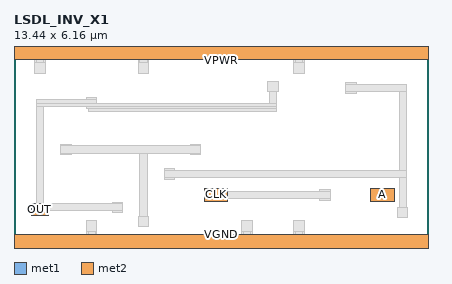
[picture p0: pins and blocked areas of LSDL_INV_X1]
MACRO LSDL_INV_X1
 CLASS CORE ;
 FOREIGN LSDL_INV_X1 0 0 ;
 SIZE 13.44 BY 6.16 ;
 ORIGIN 0 0 ;
 SYMMETRY X Y R90 ;
 SITE unit ;
  PIN VPWR
   DIRECTION INOUT ;
   USE POWER ;
   SHAPE ABUTMENT ;
    PORT
     CLASS CORE ;
       LAYER met1 ;
        RECT 0.00000000 5.92000000 13.44000000 6.40000000 ;
       LAYER met2 ;
        RECT 0.00000000 5.92000000 13.44000000 6.40000000 ;
    END
  END VPWR

  PIN VGND
   DIRECTION INOUT ;
   USE GROUND ;
   SHAPE ABUTMENT ;
    PORT
     CLASS CORE ;
       LAYER met1 ;
        RECT 0.00000000 -0.24000000 13.44000000 0.24000000 ;
       LAYER met2 ;
        RECT 0.00000000 -0.24000000 13.44000000 0.24000000 ;
    END
  END VGND

  PIN OUT
   DIRECTION OUTPUT ;
   USE SIGNAL ;
   SHAPE ABUTMENT ;
    PORT
     CLASS CORE ;
       LAYER met2 ;
        RECT 0.56000000 0.86000000 1.12000000 1.26000000 ;
    END
  END OUT

  PIN CLK
   DIRECTION INPUT ;
   USE SIGNAL ;
   SHAPE ABUTMENT ;
    PORT
     CLASS CORE ;
       LAYER met2 ;
        RECT 6.16000000 1.32700000 6.92000000 1.72700000 ;
    END
  END CLK

  PIN A
   DIRECTION INPUT ;
   USE SIGNAL ;
   SHAPE ABUTMENT ;
    PORT
     CLASS CORE ;
       LAYER met2 ;
        RECT 11.56000000 1.32700000 12.32000000 1.72700000 ;
    END
  END A

 OBS
    LAYER polycont ;
     RECT 6.61000000 1.41700000 6.83000000 1.63700000 ;
     RECT 9.97000000 1.41700000 10.19000000 1.63700000 ;
     RECT 3.25000000 1.01200000 3.47000000 1.23200000 ;
     RECT 8.29000000 4.92700000 8.51000000 5.14700000 ;
     RECT 4.93000000 2.09200000 5.15000000 2.31200000 ;
     RECT 11.65000000 1.41700000 11.87000000 1.63700000 ;
     RECT 1.57000000 2.89000000 1.79000000 3.11000000 ;

    LAYER pdiffc ;
     RECT 2.41000000 4.39000000 2.63000000 4.61000000 ;
     RECT 0.73000000 5.53000000 0.95000000 5.75000000 ;
     RECT 4.09000000 5.53000000 4.31000000 5.75000000 ;
     RECT 9.13000000 5.53000000 9.35000000 5.75000000 ;
     RECT 10.81000000 4.89000000 11.03000000 5.11000000 ;
     RECT 5.77000000 2.89000000 5.99000000 3.11000000 ;

    LAYER ndiffc ;
     RECT 0.73000000 0.95000000 0.95000000 1.17000000 ;
     RECT 12.49000000 0.85000000 12.71000000 1.07000000 ;
     RECT 2.41000000 0.41000000 2.63000000 0.63000000 ;
     RECT 7.45000000 0.41000000 7.67000000 0.63000000 ;
     RECT 9.13000000 0.41000000 9.35000000 0.63000000 ;
     RECT 4.09000000 0.55000000 4.31000000 0.77000000 ;

    LAYER met1 ;
     RECT 2.35000000 0.24000000 2.40500000 0.35000000 ;
     RECT 2.63500000 0.24000000 2.69000000 0.35000000 ;
     RECT 7.39000000 0.24000000 7.44500000 0.35000000 ;
     RECT 7.67500000 0.24000000 7.73000000 0.35000000 ;
     RECT 9.07000000 0.24000000 9.12500000 0.35000000 ;
     RECT 9.35500000 0.24000000 9.41000000 0.35000000 ;
     RECT 0.67000000 5.81000000 0.72500000 5.92000000 ;
     RECT 0.95500000 5.81000000 1.01000000 5.92000000 ;
     RECT 4.03000000 5.81000000 4.08500000 5.92000000 ;
     RECT 4.31500000 5.81000000 4.37000000 5.92000000 ;
     RECT 9.07000000 5.81000000 9.12500000 5.92000000 ;
     RECT 9.35500000 5.81000000 9.41000000 5.92000000 ;
     RECT 6.52000000 1.32700000 6.92000000 1.41200000 ;
     RECT 9.91000000 1.35700000 10.25000000 1.41200000 ;
     RECT 6.52000000 1.41200000 10.25000000 1.64200000 ;
     RECT 9.91000000 1.64200000 10.25000000 1.69700000 ;
     RECT 6.52000000 1.64200000 6.92000000 1.72700000 ;
     RECT 0.64000000 0.86000000 1.04000000 1.00700000 ;
     RECT 3.19000000 0.95200000 3.53000000 1.00700000 ;
     RECT 0.64000000 1.00700000 3.53000000 1.23700000 ;
     RECT 0.64000000 1.23700000 1.04000000 1.26000000 ;
     RECT 3.19000000 1.23700000 3.53000000 1.29200000 ;
     RECT 2.40500000 4.24700000 8.51500000 4.33000000 ;
     RECT 0.72500000 1.26000000 0.95500000 4.38500000 ;
     RECT 2.35000000 4.33000000 8.51500000 4.38500000 ;
     RECT 0.72500000 4.38500000 8.51500000 4.47700000 ;
     RECT 0.72500000 4.47700000 2.69000000 4.61500000 ;
     RECT 2.35000000 4.61500000 2.69000000 4.67000000 ;
     RECT 8.28500000 4.47700000 8.51500000 4.86700000 ;
     RECT 8.23000000 4.86700000 8.57000000 5.20700000 ;
     RECT 0.67000000 5.47000000 1.01000000 5.81000000 ;
     RECT 4.03000000 5.47000000 4.37000000 5.81000000 ;
     RECT 9.07000000 5.47000000 9.41000000 5.81000000 ;
     RECT 0.72500000 5.81000000 0.95500000 5.92000000 ;
     RECT 4.08500000 5.81000000 4.31500000 5.92000000 ;
     RECT 9.12500000 5.81000000 9.35500000 5.92000000 ;
     RECT 0.00000000 5.92000000 13.44000000 6.40000000 ;
     RECT 12.43000000 0.79000000 12.77000000 1.13000000 ;
     RECT 4.87000000 2.03200000 5.21000000 2.08700000 ;
     RECT 12.48500000 1.13000000 12.71500000 2.08700000 ;
     RECT 4.87000000 2.08700000 12.71500000 2.31700000 ;
     RECT 4.87000000 2.31700000 5.21000000 2.37200000 ;
     RECT 10.75000000 4.83000000 11.09000000 4.88500000 ;
     RECT 12.48500000 2.31700000 12.71500000 4.88500000 ;
     RECT 10.75000000 4.88500000 12.71500000 5.11500000 ;
     RECT 10.75000000 5.11500000 11.09000000 5.17000000 ;
     RECT 0.00000000 -0.24000000 13.44000000 0.24000000 ;
     RECT 2.40500000 0.24000000 2.63500000 0.35000000 ;
     RECT 7.44500000 0.24000000 7.67500000 0.35000000 ;
     RECT 9.12500000 0.24000000 9.35500000 0.35000000 ;
     RECT 2.35000000 0.35000000 2.69000000 0.69000000 ;
     RECT 7.39000000 0.35000000 7.73000000 0.69000000 ;
     RECT 9.07000000 0.35000000 9.41000000 0.69000000 ;
     RECT 11.56000000 1.32700000 11.96000000 1.72700000 ;
     RECT 4.03000000 0.49000000 4.37000000 0.83000000 ;
     RECT 1.51000000 2.83000000 1.85000000 2.88500000 ;
     RECT 4.08500000 0.83000000 4.31500000 2.88500000 ;
     RECT 5.71000000 2.83000000 6.05000000 2.88500000 ;
     RECT 1.51000000 2.88500000 6.05000000 3.11500000 ;
     RECT 1.51000000 3.11500000 1.85000000 3.17000000 ;
     RECT 5.71000000 3.11500000 6.05000000 3.17000000 ;

    LAYER via1 ;
     RECT 6.59000000 1.39700000 6.85000000 1.65700000 ;
     RECT 0.71000000 0.93000000 0.97000000 1.19000000 ;
     RECT 0.71000000 6.03000000 0.97000000 6.29000000 ;
     RECT 2.39000000 6.03000000 2.65000000 6.29000000 ;
     RECT 4.07000000 6.03000000 4.33000000 6.29000000 ;
     RECT 5.75000000 6.03000000 6.01000000 6.29000000 ;
     RECT 7.43000000 6.03000000 7.69000000 6.29000000 ;
     RECT 9.11000000 6.03000000 9.37000000 6.29000000 ;
     RECT 10.79000000 6.03000000 11.05000000 6.29000000 ;
     RECT 12.47000000 6.03000000 12.73000000 6.29000000 ;
     RECT 0.71000000 -0.13000000 0.97000000 0.13000000 ;
     RECT 2.39000000 -0.13000000 2.65000000 0.13000000 ;
     RECT 4.07000000 -0.13000000 4.33000000 0.13000000 ;
     RECT 5.75000000 -0.13000000 6.01000000 0.13000000 ;
     RECT 7.43000000 -0.13000000 7.69000000 0.13000000 ;
     RECT 9.11000000 -0.13000000 9.37000000 0.13000000 ;
     RECT 10.79000000 -0.13000000 11.05000000 0.13000000 ;
     RECT 12.47000000 -0.13000000 12.73000000 0.13000000 ;
     RECT 11.63000000 1.39700000 11.89000000 1.65700000 ;

    LAYER met2 ;
     RECT 6.52000000 1.32700000 6.92000000 1.72700000 ;
     RECT 0.64000000 0.86000000 1.04000000 1.26000000 ;
     RECT 0.00000000 5.92000000 13.44000000 6.40000000 ;
     RECT 0.00000000 -0.24000000 13.44000000 0.24000000 ;
     RECT 11.56000000 1.32700000 11.96000000 1.72700000 ;

 END
END LSDL_INV_X1
